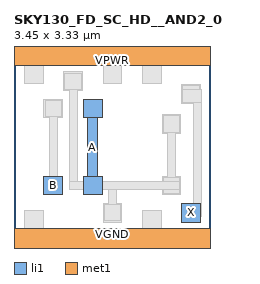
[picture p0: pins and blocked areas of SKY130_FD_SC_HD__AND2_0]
MACRO SKY130_FD_SC_HD__AND2_0
 CLASS CORE ;
 FOREIGN SKY130_FD_SC_HD__AND2_0 0 0 ;
 SIZE 3.45 BY 3.33 ;
 ORIGIN 0 0 ;
 SYMMETRY X Y R90 ;
 SITE unit ;
  PIN VPWR
   DIRECTION INOUT ;
   USE POWER ;
   SHAPE ABUTMENT ;
    PORT
     CLASS CORE ;
       LAYER li1 ;
        RECT 0.00000000 3.09000000 3.45000000 3.57000000 ;
       LAYER met1 ;
        RECT 0.00000000 3.09000000 3.45000000 3.57000000 ;
    END
  END VPWR

  PIN VGND
   DIRECTION INOUT ;
   USE POWER ;
   SHAPE ABUTMENT ;
    PORT
     CLASS CORE ;
       LAYER li1 ;
        RECT 0.00000000 -0.24000000 3.45000000 0.24000000 ;
       LAYER met1 ;
        RECT 0.00000000 -0.24000000 3.45000000 0.24000000 ;
    END
  END VGND

  PIN X
   DIRECTION INOUT ;
   USE SIGNAL ;
   SHAPE ABUTMENT ;
    PORT
     CLASS CORE ;
       LAYER li1 ;
        RECT 2.94000000 0.35000000 3.27000000 0.68000000 ;
    END
  END X

  PIN B
   DIRECTION INOUT ;
   USE SIGNAL ;
   SHAPE ABUTMENT ;
    PORT
     CLASS CORE ;
       LAYER li1 ;
        RECT 0.52500000 0.82500000 0.85500000 1.15500000 ;
    END
  END B

  PIN A
   DIRECTION INOUT ;
   USE SIGNAL ;
   SHAPE ABUTMENT ;
    PORT
     CLASS CORE ;
       LAYER li1 ;
        RECT 1.21500000 0.82500000 1.54500000 1.15500000 ;
        RECT 1.29500000 1.15500000 1.46500000 2.17500000 ;
        RECT 1.21500000 2.17500000 1.54500000 2.50500000 ;
    END
  END A

 OBS
    LAYER polycont ;
     RECT 0.60500000 0.90500000 0.77500000 1.07500000 ;
     RECT 1.29500000 0.90500000 1.46500000 1.07500000 ;
     RECT 2.67500000 0.90500000 2.84500000 1.07500000 ;
     RECT 2.67500000 1.98500000 2.84500000 2.15500000 ;
     RECT 0.60500000 2.25500000 0.77500000 2.42500000 ;
     RECT 1.29500000 2.25500000 1.46500000 2.42500000 ;

    LAYER pdiffc ;
     RECT 3.02000000 2.51000000 3.19000000 2.68000000 ;
     RECT 0.95000000 2.73000000 1.12000000 2.90000000 ;
     RECT 0.26000000 2.86000000 0.43000000 3.03000000 ;
     RECT 1.64000000 2.86000000 1.81000000 3.03000000 ;
     RECT 2.33000000 2.86000000 2.50000000 3.03000000 ;

    LAYER ndiffc ;
     RECT 0.26000000 0.30000000 0.43000000 0.47000000 ;
     RECT 2.33000000 0.30000000 2.50000000 0.47000000 ;
     RECT 1.64000000 0.43000000 1.81000000 0.60000000 ;
     RECT 3.02000000 0.43000000 3.19000000 0.60000000 ;

    LAYER li1 ;
     RECT 0.00000000 -0.24000000 3.45000000 0.24000000 ;
     RECT 0.18000000 0.24000000 0.51000000 0.55000000 ;
     RECT 2.25000000 0.24000000 2.58000000 0.55000000 ;
     RECT 1.56000000 0.35000000 1.89000000 0.68000000 ;
     RECT 2.94000000 0.35000000 3.27000000 0.68000000 ;
     RECT 0.52500000 0.82500000 0.85500000 1.15500000 ;
     RECT 2.59500000 0.82500000 2.92500000 1.15500000 ;
     RECT 2.59500000 1.90500000 2.92500000 2.23500000 ;
     RECT 0.52500000 2.17500000 0.85500000 2.50500000 ;
     RECT 1.21500000 0.82500000 1.54500000 1.15500000 ;
     RECT 1.29500000 1.15500000 1.46500000 2.17500000 ;
     RECT 1.21500000 2.17500000 1.54500000 2.50500000 ;
     RECT 2.94000000 2.43000000 3.27000000 2.76000000 ;
     RECT 0.87000000 2.65000000 1.20000000 2.98000000 ;
     RECT 0.18000000 2.78000000 0.51000000 3.09000000 ;
     RECT 1.56000000 2.78000000 1.89000000 3.09000000 ;
     RECT 2.25000000 2.78000000 2.58000000 3.09000000 ;
     RECT 0.00000000 3.09000000 3.45000000 3.57000000 ;

    LAYER viali ;
     RECT 2.33000000 -0.08500000 2.50000000 0.08500000 ;
     RECT 1.64000000 0.43000000 1.81000000 0.60000000 ;
     RECT 3.02000000 0.43000000 3.19000000 0.60000000 ;
     RECT 0.60500000 0.90500000 0.77500000 1.07500000 ;
     RECT 2.67500000 0.90500000 2.84500000 1.07500000 ;
     RECT 2.67500000 1.98500000 2.84500000 2.15500000 ;
     RECT 0.60500000 2.25500000 0.77500000 2.42500000 ;
     RECT 3.02000000 2.51000000 3.19000000 2.68000000 ;
     RECT 0.95000000 2.73000000 1.12000000 2.90000000 ;
     RECT 2.33000000 3.24500000 2.50000000 3.41500000 ;

    LAYER met1 ;
     RECT 0.00000000 -0.24000000 3.45000000 0.24000000 ;
     RECT 0.54500000 0.84500000 0.83500000 1.13500000 ;
     RECT 0.62000000 1.13500000 0.76000000 2.19500000 ;
     RECT 0.54500000 2.19500000 0.83500000 2.48500000 ;
     RECT 2.96000000 0.37000000 3.25000000 0.44500000 ;
     RECT 2.96000000 0.44500000 3.29000000 0.66000000 ;
     RECT 3.15000000 0.66000000 3.29000000 2.45000000 ;
     RECT 2.96000000 2.45000000 3.29000000 2.66500000 ;
     RECT 2.96000000 2.66500000 3.25000000 2.74000000 ;
     RECT 1.58000000 0.37000000 1.87000000 0.66000000 ;
     RECT 1.65500000 0.66000000 1.79500000 0.92000000 ;
     RECT 2.61500000 0.84500000 2.90500000 0.92000000 ;
     RECT 0.96500000 0.92000000 2.90500000 1.06000000 ;
     RECT 2.61500000 1.06000000 2.90500000 1.13500000 ;
     RECT 2.69000000 1.13500000 2.83000000 1.92500000 ;
     RECT 2.61500000 1.92500000 2.90500000 2.21500000 ;
     RECT 0.96500000 1.06000000 1.10500000 2.67000000 ;
     RECT 0.89000000 2.67000000 1.18000000 2.96000000 ;
     RECT 0.00000000 3.09000000 3.45000000 3.57000000 ;

    LAYER via ;


    LAYER met2 ;


    LAYER via2 ;


    LAYER met3 ;


 END
END SKY130_FD_SC_HD__AND2_0
